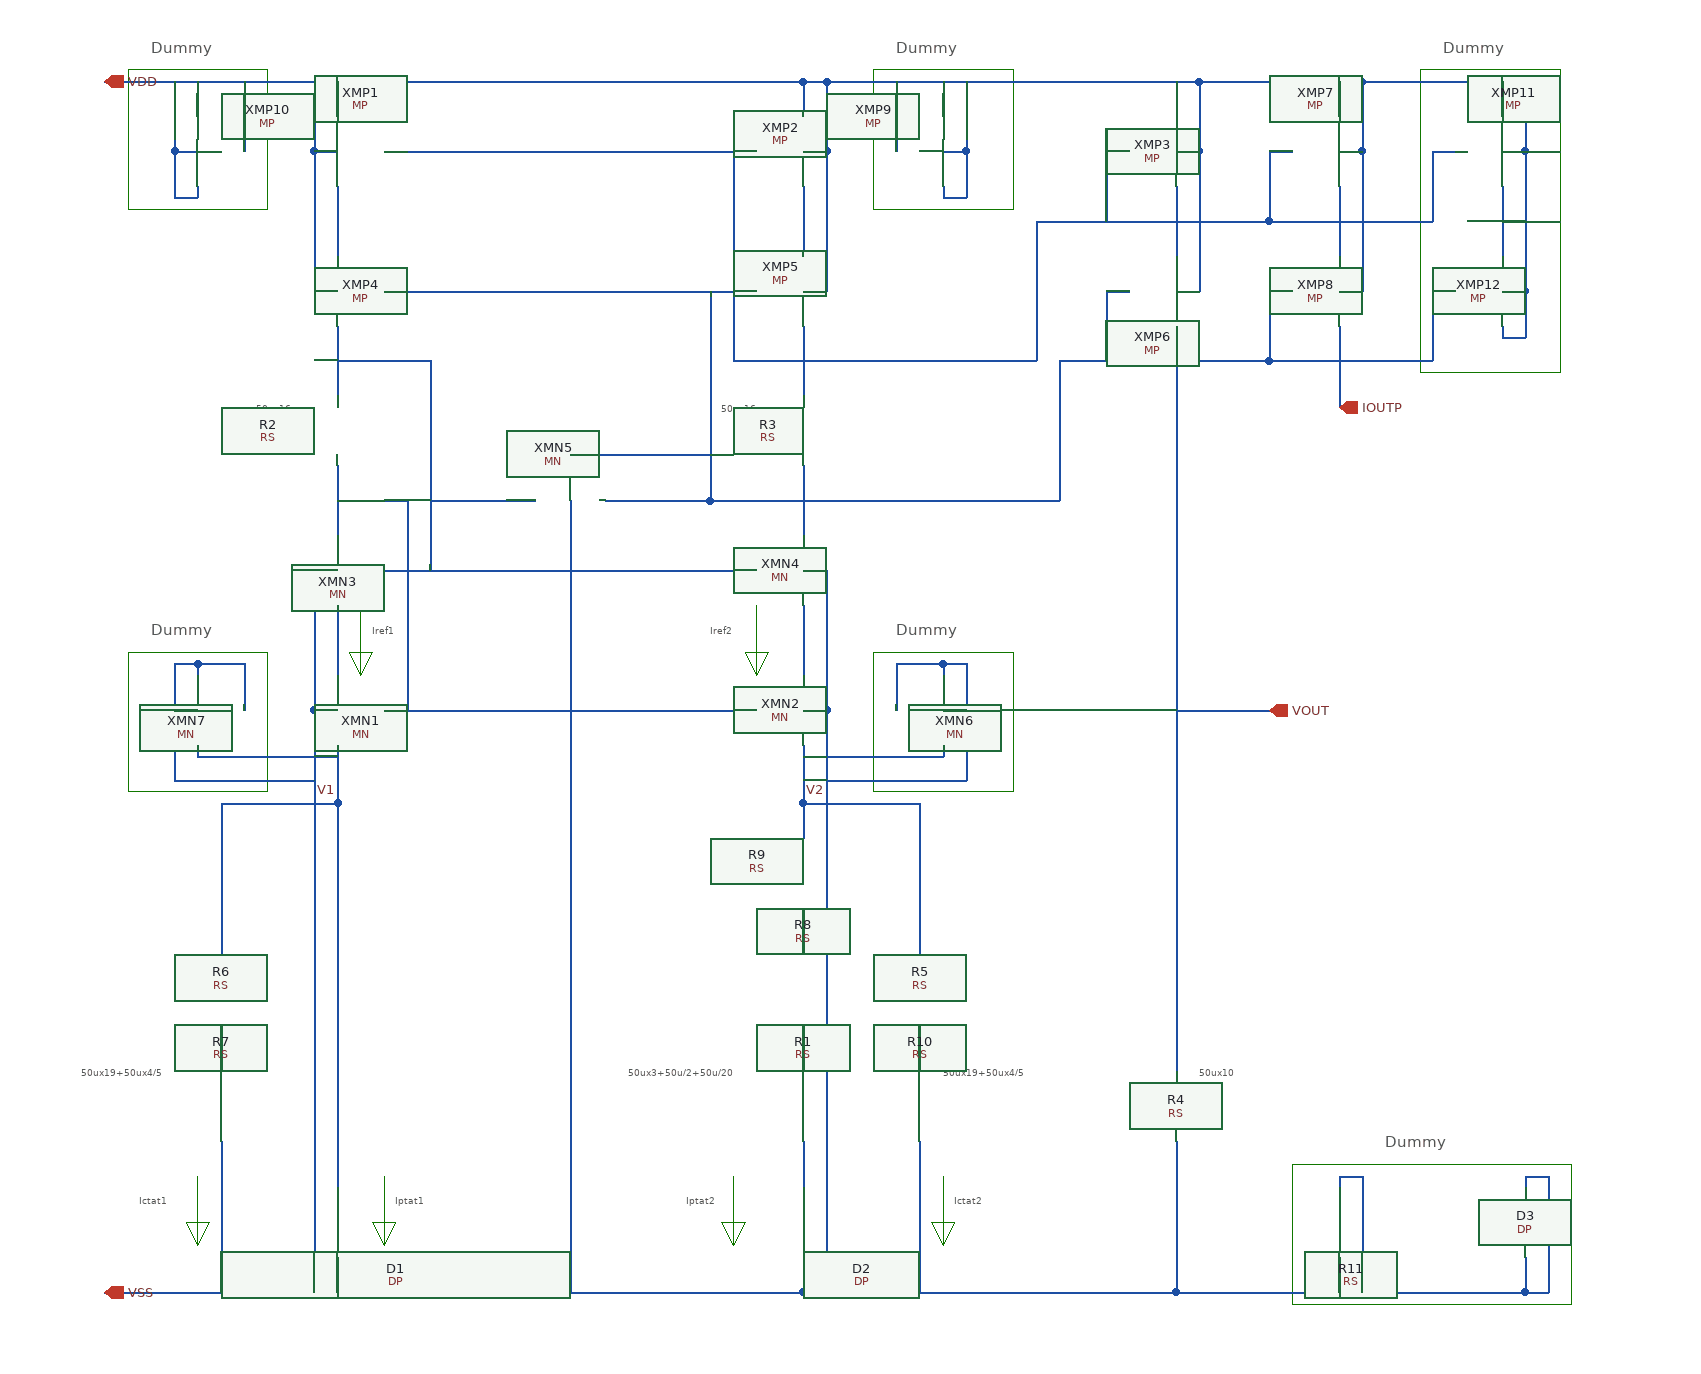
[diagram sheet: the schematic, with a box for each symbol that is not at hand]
v {xschem version=3.4.8RC file_version=1.2}
G {}
K {}
V {}
S {}
E {}
P 4 5 260 -610 260 -550 270 -570 250 -570 260 -550 {}
P 4 5 600 -610 600 -550 610 -570 590 -570 600 -550 {}
P 4 5 580 -120 580 -60 590 -80 570 -80 580 -60 {}
P 4 5 760 -120 760 -60 770 -80 750 -80 760 -60 {}
P 4 5 280 -120 280 -60 290 -80 270 -80 280 -60 {}
P 4 5 120 -120 120 -60 130 -80 110 -80 120 -60 {}
P 4 5 1060 -130 1060 -10 1300 -10 1300 -130 1060 -130 {}
P 4 5 700 -570 700 -450 820 -450 820 -570 700 -570 {}
P 4 5 60 -570 60 -450 180 -450 180 -570 60 -570 {}
P 4 5 700 -1070 700 -950 820 -950 820 -1070 700 -1070 {}
P 4 5 60 -1070 60 -950 180 -950 180 -1070 60 -1070 {}
P 4 5 1170 -1070 1170 -810 1290 -810 1290 -1070 1170 -1070 {}
T {Iref1} 270 -600 0 0 0.25 0.25 {}
T {Iref2} 560 -600 0 0 0.25 0.25 {}
T {50ux3+50u/2+50u/20} 490 -220 0 0 0.25 0.25 {}
T {50ux16} 570 -790 0 0 0.25 0.25 {}
T {50ux16} 170 -790 0 0 0.25 0.25 {}
T {50ux10} 980 -220 0 0 0.25 0.25 {}
T {50ux19+50ux4/5} 760 -220 0 0 0.25 0.25 {}
T {Iptat2} 540 -110 0 0 0.25 0.25 {}
T {Ictat2} 770 -110 0 0 0.25 0.25 {}
T {Iptat1} 290 -110 0 0 0.25 0.25 {}
T {Ictat1} 70 -110 0 0 0.25 0.25 {}
T {50ux19+50ux4/5} 20 -220 0 0 0.25 0.25 {}
T {Dummy} 1140 -160 0 0 0.4 0.4 {}
T {Dummy} 720 -600 0 0 0.4 0.4 {}
T {Dummy} 80 -600 0 0 0.4 0.4 {}
T {Dummy} 720 -1100 0 0 0.4 0.4 {}
T {Dummy} 80 -1100 0 0 0.4 0.4 {}
T {Dummy} 1190 -1100 0 0 0.4 0.4 {}
N 640 -1060 640 -1030 {lab=VDD}
N 40 -1060 640 -1060 {lab=VDD}
N 240 -1060 240 -1030 {lab=VDD}
N 640 -1000 660 -1000 {lab=VDD}
N 660 -1060 660 -1000 {lab=VDD}
N 640 -1060 660 -1060 {lab=VDD}
N 220 -1000 240 -1000 {lab=VDD}
N 220 -1060 220 -1000 {lab=VDD}
N 280 -1000 600 -1000 {lab=#net1}
N 240 -490 240 -440 {lab=V1}
N 640 -490 640 -440 {lab=V2}
N 640 -520 660 -520 {lab=VSS}
N 660 -520 660 -20 {lab=VSS}
N 220 -520 240 -520 {lab=VSS}
N 220 -520 220 -20 {lab=VSS}
N 280 -520 600 -520 {lab=#net2}
N 300 -700 300 -520 {lab=#net2}
N 240 -700 300 -700 {lab=#net2}
N 580 -1000 580 -960 {lab=#net1}
N 580 -960 580 -940 {lab=#net1}
N 580 -820 640 -820 {lab=#net1}
N 640 -440 640 -410 {lab=V2}
N 640 -150 640 -110 {lab=#net3}
N 240 -440 240 -110 {lab=V1}
N 640 -50 640 -20 {lab=VSS}
N 40 -20 640 -20 {lab=VSS}
N 240 -50 240 -20 {lab=VSS}
N 640 -820 840 -820 {lab=#net1}
N 900 -1000 920 -1000 {lab=#net1}
N 660 -1060 980 -1060 {lab=VDD}
N 980 -1060 980 -1000 {lab=VDD}
N 960 -1000 980 -1000 {lab=VDD}
N 960 -1060 960 -1030 {lab=VDD}
N 960 -850 960 -780 {lab=VOUT}
N 240 -970 240 -910 {lab=#net4}
N 640 -970 640 -910 {lab=#net5}
N 280 -880 600 -880 {lab=#net6}
N 240 -610 240 -550 {lab=#net7}
N 640 -610 640 -550 {lab=#net8}
N 640 -640 660 -640 {lab=VSS}
N 280 -640 600 -640 {lab=#net9}
N 220 -640 240 -640 {lab=VSS}
N 640 -850 640 -790 {lab=#net1}
N 640 -880 660 -880 {lab=VDD}
N 220 -880 240 -880 {lab=VDD}
N 560 -880 560 -700 {lab=#net6}
N 560 -700 640 -700 {lab=#net6}
N 320 -820 320 -640 {lab=#net9}
N 240 -820 320 -820 {lab=#net9}
N 660 -920 660 -880 {lab=VDD}
N 220 -920 220 -880 {lab=VDD}
N 220 -640 220 -600 {lab=VSS}
N 660 -640 660 -600 {lab=VSS}
N 220 -1000 220 -920 {lab=VDD}
N 660 -1000 660 -920 {lab=VDD}
N 220 -600 220 -520 {lab=VSS}
N 660 -600 660 -520 {lab=VSS}
N 640 -20 660 -20 {lab=VSS}
N 240 -850 240 -790 {lab=#net9}
N 240 -730 240 -670 {lab=#net2}
N 640 -730 640 -670 {lab=#net6}
N 580 -940 580 -820 {lab=#net1}
N 960 -970 960 -910 {lab=#net10}
N 640 -700 860 -700 {lab=#net6}
N 960 -880 980 -880 {lab=VDD}
N 980 -1000 980 -880 {lab=VDD}
N 860 -820 1040 -820 {lab=#net6}
N 860 -820 860 -700 {lab=#net6}
N 960 -150 960 -20 {lab=VSS}
N 660 -20 960 -20 {lab=VSS}
N 960 -780 960 -210 {lab=VOUT}
N 960 -520 1040 -520 {lab=VOUT}
N 470 -700 560 -700 {lab=#net6}
N 440 -740 560 -740 {lab=#net6}
N 320 -700 410 -700 {lab=#net9}
N 440 -700 440 -20 {lab=VSS}
N 840 -940 1040 -940 {lab=#net1}
N 840 -940 840 -820 {lab=#net1}
N 900 -1000 900 -940 {lab=#net1}
N 900 -880 900 -820 {lab=#net6}
N 900 -880 920 -880 {lab=#net6}
N 640 -440 740 -440 {lab=V2}
N 740 -150 740 -20 {lab=VSS}
N 140 -440 240 -440 {lab=V1}
N 140 -440 140 -310 {lab=V1}
N 140 -250 140 -210 {lab=#net11}
N 1040 -1000 1060 -1000 {lab=#net1}
N 1120 -1060 1120 -1000 {lab=VDD}
N 1100 -1000 1120 -1000 {lab=VDD}
N 1100 -1060 1100 -1030 {lab=VDD}
N 1100 -850 1100 -780 {lab=IOUTP}
N 1100 -970 1100 -910 {lab=#net12}
N 1100 -880 1120 -880 {lab=VDD}
N 1120 -1000 1120 -880 {lab=VDD}
N 1040 -1000 1040 -940 {lab=#net1}
N 1040 -880 1040 -820 {lab=#net6}
N 1040 -880 1060 -880 {lab=#net6}
N 980 -1060 1120 -1060 {lab=VDD}
N 140 -150 140 -20 {lab=VSS}
N 640 -350 640 -310 {lab=#net13}
N 640 -250 640 -210 {lab=#net14}
N 740 -440 740 -310 {lab=V2}
N 740 -250 740 -210 {lab=#net15}
N 1260 -50 1260 -20 {lab=VSS}
N 960 -20 1260 -20 {lab=VSS}
N 1100 -50 1100 -20 {lab=VSS}
N 1100 -120 1100 -110 {lab=VSS}
N 1100 -120 1120 -120 {lab=VSS}
N 1120 -120 1120 -20 {lab=VSS}
N 1260 -120 1260 -110 {lab=VSS}
N 1260 -120 1280 -120 {lab=VSS}
N 1280 -120 1280 -20 {lab=VSS}
N 1260 -20 1280 -20 {lab=VSS}
N 760 -490 760 -480 {lab=V2}
N 720 -560 720 -520 {lab=VSS}
N 720 -560 760 -560 {lab=VSS}
N 760 -560 760 -550 {lab=VSS}
N 760 -560 780 -560 {lab=VSS}
N 780 -560 780 -460 {lab=VSS}
N 660 -460 780 -460 {lab=VSS}
N 640 -480 760 -480 {lab=V2}
N 120 -490 120 -480 {lab=V1}
N 160 -560 160 -520 {lab=VSS}
N 120 -560 160 -560 {lab=VSS}
N 120 -560 120 -550 {lab=VSS}
N 100 -560 120 -560 {lab=VSS}
N 100 -560 100 -460 {lab=VSS}
N 100 -460 220 -460 {lab=VSS}
N 120 -480 240 -480 {lab=V1}
N 720 -1060 720 -1000 {lab=VDD}
N 760 -1060 760 -1030 {lab=VDD}
N 760 -1000 780 -1000 {lab=VDD}
N 780 -1060 780 -1000 {lab=VDD}
N 760 -970 760 -960 {lab=VDD}
N 760 -960 780 -960 {lab=VDD}
N 780 -1000 780 -960 {lab=VDD}
N 160 -1060 160 -1000 {lab=VDD}
N 120 -1060 120 -1030 {lab=VDD}
N 100 -1000 120 -1000 {lab=VDD}
N 100 -1060 100 -1000 {lab=VDD}
N 120 -970 120 -960 {lab=VDD}
N 100 -960 120 -960 {lab=VDD}
N 100 -1000 100 -960 {lab=VDD}
N 1240 -1000 1260 -1000 {lab=VDD}
N 1240 -970 1240 -910 {lab=VDD}
N 1240 -880 1260 -880 {lab=VDD}
N 1260 -1000 1260 -880 {lab=VDD}
N 1040 -940 1180 -940 {lab=#net1}
N 1180 -1000 1180 -940 {lab=#net1}
N 1180 -1000 1200 -1000 {lab=#net1}
N 1040 -820 1180 -820 {lab=#net6}
N 1180 -880 1180 -820 {lab=#net6}
N 1180 -880 1200 -880 {lab=#net6}
N 1240 -850 1240 -840 {lab=VDD}
N 1240 -840 1260 -840 {lab=VDD}
N 1260 -880 1260 -840 {lab=VDD}
N 1120 -1060 1260 -1060 {lab=VDD}
N 1260 -1060 1260 -1000 {lab=VDD}
N 1240 -1060 1240 -1030 {lab=VDD}
N 1240 -940 1260 -940 {lab=VDD}
N 100 -520 120 -520 {lab=VSS}
N 760 -520 780 -520 {lab=VSS}
C {MP.sym} 280 -1000 0 1 {name=XMP1 model=PMOS w=20u l=4u m=4 as=0 ad=0 ps=0 pd=0 nrd=0 nrs=0}
C {MN.sym} 280 -520 0 1 {name=XMN1 model=NMOS w=10u l=4u m=4 as=0 ad=0 ps=0 pd=0 nrd=0 nrs=0}
C {MP.sym} 600 -1000 0 0 {name=XMP2 model=PMOS w=20u l=4u m=4 as=0 ad=0 ps=0 pd=0 nrd=0 nrs=0}
C {MN.sym} 600 -520 0 0 {name=XMN2 model=NMOS w=10u l=4u m=4 as=0 ad=0 ps=0 pd=0 nrd=0 nrs=0}
C {devices/iopin.sym} 40 -1060 0 1 {name=p1 lab=VDD}
C {devices/iopin.sym} 40 -20 0 1 {name=p2 lab=VSS}
C {MP.sym} 920 -1000 0 0 {name=XMP3 model=PMOS w=20u l=4u m=18 as=0 ad=0 ps=0 pd=0 nrd=0 nrs=0}
C {devices/lab_wire.sym} 240 -450 0 0 {name=p4 sig_type=std_logic lab=V1}
C {devices/lab_wire.sym} 640 -450 0 1 {name=p5 sig_type=std_logic lab=V2}
C {MP.sym} 280 -880 0 1 {name=XMP4 model=PMOS w=20u l=1u m=4 as=0 ad=0 ps=0 pd=0 nrd=0 nrs=0}
C {MP.sym} 600 -880 0 0 {name=XMP5 model=PMOS w=20u l=1u m=4 as=0 ad=0 ps=0 pd=0 nrd=0 nrs=0}
C {MN.sym} 280 -640 0 1 {name=XMN3 model=NMOS w=10u l=1u m=4 as=0 ad=0 ps=0 pd=0 nrd=0 nrs=0}
C {MN.sym} 600 -640 0 0 {name=XMN4 model=NMOS w=10u l=1u m=4 as=0 ad=0 ps=0 pd=0 nrd=0 nrs=0}
C {MP.sym} 920 -880 0 0 {name=XMP6 model=PMOS w=20u l=1u m=18 as=0 ad=0 ps=0 pd=0 nrd=0 nrs=0}
C {devices/opin.sym} 1040 -520 0 0 {name=p3 lab=VOUT}
C {MN.sym} 440 -740 1 0 {name=XMN5 model=NMOS w=4u l=4u m=1 as=0 ad=0 ps=0 pd=0 nrd=0 nrs=0}
C {RS.sym} 640 -210 0 0 {name=R1
w=4e-6
l=150e-6
R=1
model=F_RS
spiceprefix=X
tc1=0
tc2=0}
C {RS.sym} 960 -210 0 0 {name=R4
w=4e-6
l=500e-6
R=1
model=F_RS
spiceprefix=X
tc1=0
tc2=0}
C {RS.sym} 240 -790 0 0 {name=R2
w=4e-6
l=800e-6
R=1
model=F_RS
spiceprefix=X
tc1=0
tc2=0}
C {RS.sym} 640 -790 0 0 {name=R3
w=4e-6
l=800e-6
R=1
model=F_RS
spiceprefix=X
tc1=0
tc2=0}
C {RS.sym} 140 -310 0 0 {name=R6
w=4e-6
l=200e-6
m=5
R=1
model=F_RS
spiceprefix=X
tc1=0
tc2=0}
C {MP.sym} 1060 -1000 0 0 {name=XMP7 model=PMOS w=20u l=4u m=4 as=0 ad=0 ps=0 pd=0 nrd=0 nrs=0}
C {MP.sym} 1060 -880 0 0 {name=XMP8 model=PMOS w=20u l=1u m=4 as=0 ad=0 ps=0 pd=0 nrd=0 nrs=0}
C {devices/opin.sym} 1100 -780 1 0 {name=p6 lab=IOUTP}
C {RS.sym} 140 -210 0 0 {name=R7
w=4e-6
l=950e-6
R=1
model=F_RS
spiceprefix=X
tc1=0
tc2=0}
C {RS.sym} 640 -310 0 0 {name=R8
w=4e-6
l=50e-6
m=2
R=1
model=F_RS
spiceprefix=X
tc1=0
tc2=0}
C {RS.sym} 640 -410 0 0 {name=R9
w=4e-6
l=50e-6
R=1
m=20
model=F_RS
spiceprefix=X
tc1=0
tc2=0}
C {RS.sym} 740 -310 0 0 {name=R5
w=4e-6
l=200e-6
m=5
R=1
model=F_RS
spiceprefix=X
tc1=0
tc2=0}
C {RS.sym} 740 -210 0 0 {name=R10
w=4e-6
l=950e-6
R=1
model=F_RS
spiceprefix=X
tc1=0
tc2=0}
C {RS.sym} 1100 -110 0 0 {name=R11
w=4e-6
l=50e-6
m=11
R=1
model=F_RS
spiceprefix=X
tc1=0
tc2=0}
C {DP.sym} 240 -50 2 0 {name=D1
model=DP
w=3.6u
l=3.6u
a="expr_eng( @w * @l )"
p="expr_eng( 2 * ( @w + @l ) )"
spiceprefix=D
m=1}
C {DP.sym} 640 -50 2 0 {name=D2
model=DP
w=3.6u
l=3.6u
a="expr_eng( @w * @l )"
p="expr_eng( 2 * ( @w + @l ) )"
spiceprefix=D
m=8}
C {DP.sym} 1260 -50 2 0 {name=D3
model=DP
w=3.6u
l=3.6u
a="expr_eng( @w * @l )"
p="expr_eng( 2 * ( @w + @l ) )"
spiceprefix=D
m=19}
C {MN.sym} 720 -520 0 0 {name=XMN6 model=NMOS w=10u l=4u m=2 as=0 ad=0 ps=0 pd=0 nrd=0 nrs=0}
C {MN.sym} 160 -520 0 1 {name=XMN7 model=NMOS w=10u l=4u m=2 as=0 ad=0 ps=0 pd=0 nrd=0 nrs=0}
C {MP.sym} 720 -1000 0 0 {name=XMP9 model=PMOS w=20u l=4u m=4 as=0 ad=0 ps=0 pd=0 nrd=0 nrs=0}
C {MP.sym} 160 -1000 0 1 {name=XMP10 model=PMOS w=20u l=4u m=4 as=0 ad=0 ps=0 pd=0 nrd=0 nrs=0}
C {MP.sym} 1200 -1000 0 0 {name=XMP11 model=PMOS w=20u l=4u m=2 as=0 ad=0 ps=0 pd=0 nrd=0 nrs=0}
C {MP.sym} 1200 -880 0 0 {name=XMP12 model=PMOS w=20u l=1u m=2 as=0 ad=0 ps=0 pd=0 nrd=0 nrs=0}
